VERSION 5.7 ;
  NOWIREEXTENSIONATPIN ON ;
  DIVIDERCHAR "/" ;
  BUSBITCHARS "[]" ;
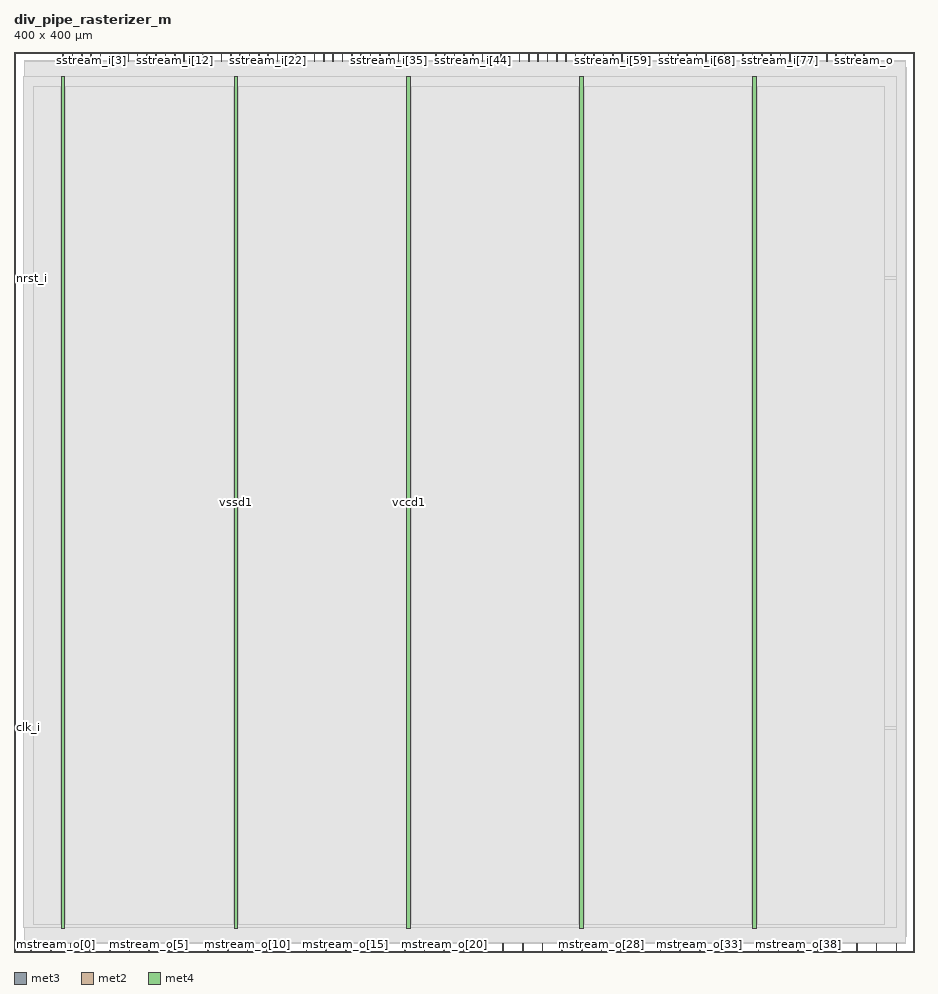
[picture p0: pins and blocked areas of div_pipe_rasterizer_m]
MACRO div_pipe_rasterizer_m
  CLASS BLOCK ;
  FOREIGN div_pipe_rasterizer_m ;
  ORIGIN 0.000 0.000 ;
  SIZE 400.000 BY 400.000 ;
  PIN clk_i
    DIRECTION INPUT ;
    USE SIGNAL ;
    ANTENNAGATEAREA 0.852000 ;
    PORT
      LAYER met3 ;
        RECT 0.000 99.320 4.000 99.920 ;
    END
  END clk_i
  PIN mstream_i
    DIRECTION INPUT ;
    USE SIGNAL ;
    ANTENNAGATEAREA 0.196500 ;
    PORT
      LAYER met2 ;
        RECT 7.450 0.000 7.730 4.000 ;
    END
  END mstream_i
  PIN mstream_o[0]
    DIRECTION OUTPUT TRISTATE ;
    USE SIGNAL ;
    ANTENNADIFFAREA 2.673000 ;
    PORT
      LAYER met2 ;
        RECT 16.190 0.000 16.470 4.000 ;
    END
  END mstream_o[0]
  PIN mstream_o[10]
    DIRECTION OUTPUT TRISTATE ;
    USE SIGNAL ;
    ANTENNADIFFAREA 2.673000 ;
    PORT
      LAYER met2 ;
        RECT 103.590 0.000 103.870 4.000 ;
    END
  END mstream_o[10]
  PIN mstream_o[11]
    DIRECTION OUTPUT TRISTATE ;
    USE SIGNAL ;
    ANTENNADIFFAREA 2.673000 ;
    PORT
      LAYER met2 ;
        RECT 112.330 0.000 112.610 4.000 ;
    END
  END mstream_o[11]
  PIN mstream_o[12]
    DIRECTION OUTPUT TRISTATE ;
    USE SIGNAL ;
    ANTENNADIFFAREA 2.673000 ;
    PORT
      LAYER met2 ;
        RECT 121.070 0.000 121.350 4.000 ;
    END
  END mstream_o[12]
  PIN mstream_o[13]
    DIRECTION OUTPUT TRISTATE ;
    USE SIGNAL ;
    ANTENNADIFFAREA 2.673000 ;
    PORT
      LAYER met2 ;
        RECT 129.810 0.000 130.090 4.000 ;
    END
  END mstream_o[13]
  PIN mstream_o[14]
    DIRECTION OUTPUT TRISTATE ;
    USE SIGNAL ;
    ANTENNADIFFAREA 2.673000 ;
    PORT
      LAYER met2 ;
        RECT 138.550 0.000 138.830 4.000 ;
    END
  END mstream_o[14]
  PIN mstream_o[15]
    DIRECTION OUTPUT TRISTATE ;
    USE SIGNAL ;
    ANTENNADIFFAREA 2.673000 ;
    PORT
      LAYER met2 ;
        RECT 147.290 0.000 147.570 4.000 ;
    END
  END mstream_o[15]
  PIN mstream_o[16]
    DIRECTION OUTPUT TRISTATE ;
    USE SIGNAL ;
    ANTENNADIFFAREA 2.673000 ;
    PORT
      LAYER met2 ;
        RECT 156.030 0.000 156.310 4.000 ;
    END
  END mstream_o[16]
  PIN mstream_o[17]
    DIRECTION OUTPUT TRISTATE ;
    USE SIGNAL ;
    ANTENNADIFFAREA 2.673000 ;
    PORT
      LAYER met2 ;
        RECT 164.770 0.000 165.050 4.000 ;
    END
  END mstream_o[17]
  PIN mstream_o[18]
    DIRECTION OUTPUT TRISTATE ;
    USE SIGNAL ;
    ANTENNADIFFAREA 2.673000 ;
    PORT
      LAYER met2 ;
        RECT 173.510 0.000 173.790 4.000 ;
    END
  END mstream_o[18]
  PIN mstream_o[19]
    DIRECTION OUTPUT TRISTATE ;
    USE SIGNAL ;
    ANTENNADIFFAREA 2.673000 ;
    PORT
      LAYER met2 ;
        RECT 182.250 0.000 182.530 4.000 ;
    END
  END mstream_o[19]
  PIN mstream_o[1]
    DIRECTION OUTPUT TRISTATE ;
    USE SIGNAL ;
    ANTENNADIFFAREA 2.673000 ;
    PORT
      LAYER met2 ;
        RECT 24.930 0.000 25.210 4.000 ;
    END
  END mstream_o[1]
  PIN mstream_o[20]
    DIRECTION OUTPUT TRISTATE ;
    USE SIGNAL ;
    ANTENNADIFFAREA 2.673000 ;
    PORT
      LAYER met2 ;
        RECT 190.990 0.000 191.270 4.000 ;
    END
  END mstream_o[20]
  PIN mstream_o[21]
    DIRECTION OUTPUT TRISTATE ;
    USE SIGNAL ;
    ANTENNADIFFAREA 2.673000 ;
    PORT
      LAYER met2 ;
        RECT 199.730 0.000 200.010 4.000 ;
    END
  END mstream_o[21]
  PIN mstream_o[22]
    DIRECTION OUTPUT TRISTATE ;
    USE SIGNAL ;
    ANTENNADIFFAREA 2.673000 ;
    PORT
      LAYER met2 ;
        RECT 208.470 0.000 208.750 4.000 ;
    END
  END mstream_o[22]
  PIN mstream_o[23]
    DIRECTION OUTPUT TRISTATE ;
    USE SIGNAL ;
    ANTENNADIFFAREA 2.673000 ;
    PORT
      LAYER met2 ;
        RECT 217.210 0.000 217.490 4.000 ;
    END
  END mstream_o[23]
  PIN mstream_o[24]
    DIRECTION OUTPUT TRISTATE ;
    USE SIGNAL ;
    ANTENNADIFFAREA 2.673000 ;
    PORT
      LAYER met2 ;
        RECT 225.950 0.000 226.230 4.000 ;
    END
  END mstream_o[24]
  PIN mstream_o[25]
    DIRECTION OUTPUT TRISTATE ;
    USE SIGNAL ;
    ANTENNADIFFAREA 2.673000 ;
    PORT
      LAYER met2 ;
        RECT 234.690 0.000 234.970 4.000 ;
    END
  END mstream_o[25]
  PIN mstream_o[26]
    DIRECTION OUTPUT TRISTATE ;
    USE SIGNAL ;
    ANTENNADIFFAREA 2.673000 ;
    PORT
      LAYER met2 ;
        RECT 243.430 0.000 243.710 4.000 ;
    END
  END mstream_o[26]
  PIN mstream_o[27]
    DIRECTION OUTPUT TRISTATE ;
    USE SIGNAL ;
    ANTENNADIFFAREA 2.673000 ;
    PORT
      LAYER met2 ;
        RECT 252.170 0.000 252.450 4.000 ;
    END
  END mstream_o[27]
  PIN mstream_o[28]
    DIRECTION OUTPUT TRISTATE ;
    USE SIGNAL ;
    ANTENNADIFFAREA 2.673000 ;
    PORT
      LAYER met2 ;
        RECT 260.910 0.000 261.190 4.000 ;
    END
  END mstream_o[28]
  PIN mstream_o[29]
    DIRECTION OUTPUT TRISTATE ;
    USE SIGNAL ;
    ANTENNADIFFAREA 2.673000 ;
    PORT
      LAYER met2 ;
        RECT 269.650 0.000 269.930 4.000 ;
    END
  END mstream_o[29]
  PIN mstream_o[2]
    DIRECTION OUTPUT TRISTATE ;
    USE SIGNAL ;
    ANTENNADIFFAREA 2.673000 ;
    PORT
      LAYER met2 ;
        RECT 33.670 0.000 33.950 4.000 ;
    END
  END mstream_o[2]
  PIN mstream_o[30]
    DIRECTION OUTPUT TRISTATE ;
    USE SIGNAL ;
    ANTENNADIFFAREA 2.673000 ;
    PORT
      LAYER met2 ;
        RECT 278.390 0.000 278.670 4.000 ;
    END
  END mstream_o[30]
  PIN mstream_o[31]
    DIRECTION OUTPUT TRISTATE ;
    USE SIGNAL ;
    ANTENNADIFFAREA 2.673000 ;
    PORT
      LAYER met2 ;
        RECT 287.130 0.000 287.410 4.000 ;
    END
  END mstream_o[31]
  PIN mstream_o[32]
    DIRECTION OUTPUT TRISTATE ;
    USE SIGNAL ;
    ANTENNADIFFAREA 2.673000 ;
    PORT
      LAYER met2 ;
        RECT 295.870 0.000 296.150 4.000 ;
    END
  END mstream_o[32]
  PIN mstream_o[33]
    DIRECTION OUTPUT TRISTATE ;
    USE SIGNAL ;
    ANTENNADIFFAREA 2.673000 ;
    PORT
      LAYER met2 ;
        RECT 304.610 0.000 304.890 4.000 ;
    END
  END mstream_o[33]
  PIN mstream_o[34]
    DIRECTION OUTPUT TRISTATE ;
    USE SIGNAL ;
    ANTENNADIFFAREA 2.673000 ;
    PORT
      LAYER met2 ;
        RECT 313.350 0.000 313.630 4.000 ;
    END
  END mstream_o[34]
  PIN mstream_o[35]
    DIRECTION OUTPUT TRISTATE ;
    USE SIGNAL ;
    ANTENNADIFFAREA 2.673000 ;
    PORT
      LAYER met2 ;
        RECT 322.090 0.000 322.370 4.000 ;
    END
  END mstream_o[35]
  PIN mstream_o[36]
    DIRECTION OUTPUT TRISTATE ;
    USE SIGNAL ;
    ANTENNADIFFAREA 2.673000 ;
    PORT
      LAYER met2 ;
        RECT 330.830 0.000 331.110 4.000 ;
    END
  END mstream_o[36]
  PIN mstream_o[37]
    DIRECTION OUTPUT TRISTATE ;
    USE SIGNAL ;
    ANTENNADIFFAREA 2.673000 ;
    PORT
      LAYER met2 ;
        RECT 339.570 0.000 339.850 4.000 ;
    END
  END mstream_o[37]
  PIN mstream_o[38]
    DIRECTION OUTPUT TRISTATE ;
    USE SIGNAL ;
    ANTENNADIFFAREA 2.673000 ;
    PORT
      LAYER met2 ;
        RECT 348.310 0.000 348.590 4.000 ;
    END
  END mstream_o[38]
  PIN mstream_o[39]
    DIRECTION OUTPUT TRISTATE ;
    USE SIGNAL ;
    ANTENNADIFFAREA 2.673000 ;
    PORT
      LAYER met2 ;
        RECT 357.050 0.000 357.330 4.000 ;
    END
  END mstream_o[39]
  PIN mstream_o[3]
    DIRECTION OUTPUT TRISTATE ;
    USE SIGNAL ;
    ANTENNADIFFAREA 2.673000 ;
    PORT
      LAYER met2 ;
        RECT 42.410 0.000 42.690 4.000 ;
    END
  END mstream_o[3]
  PIN mstream_o[40]
    DIRECTION OUTPUT TRISTATE ;
    USE SIGNAL ;
    ANTENNADIFFAREA 2.673000 ;
    PORT
      LAYER met2 ;
        RECT 365.790 0.000 366.070 4.000 ;
    END
  END mstream_o[40]
  PIN mstream_o[41]
    DIRECTION OUTPUT TRISTATE ;
    USE SIGNAL ;
    ANTENNADIFFAREA 2.673000 ;
    PORT
      LAYER met2 ;
        RECT 374.530 0.000 374.810 4.000 ;
    END
  END mstream_o[41]
  PIN mstream_o[42]
    DIRECTION OUTPUT TRISTATE ;
    USE SIGNAL ;
    ANTENNADIFFAREA 2.673000 ;
    PORT
      LAYER met2 ;
        RECT 383.270 0.000 383.550 4.000 ;
    END
  END mstream_o[42]
  PIN mstream_o[43]
    DIRECTION OUTPUT TRISTATE ;
    USE SIGNAL ;
    PORT
      LAYER met2 ;
        RECT 392.010 0.000 392.290 4.000 ;
    END
  END mstream_o[43]
  PIN mstream_o[4]
    DIRECTION OUTPUT TRISTATE ;
    USE SIGNAL ;
    ANTENNADIFFAREA 2.673000 ;
    PORT
      LAYER met2 ;
        RECT 51.150 0.000 51.430 4.000 ;
    END
  END mstream_o[4]
  PIN mstream_o[5]
    DIRECTION OUTPUT TRISTATE ;
    USE SIGNAL ;
    ANTENNADIFFAREA 2.673000 ;
    PORT
      LAYER met2 ;
        RECT 59.890 0.000 60.170 4.000 ;
    END
  END mstream_o[5]
  PIN mstream_o[6]
    DIRECTION OUTPUT TRISTATE ;
    USE SIGNAL ;
    ANTENNADIFFAREA 2.673000 ;
    PORT
      LAYER met2 ;
        RECT 68.630 0.000 68.910 4.000 ;
    END
  END mstream_o[6]
  PIN mstream_o[7]
    DIRECTION OUTPUT TRISTATE ;
    USE SIGNAL ;
    ANTENNADIFFAREA 2.673000 ;
    PORT
      LAYER met2 ;
        RECT 77.370 0.000 77.650 4.000 ;
    END
  END mstream_o[7]
  PIN mstream_o[8]
    DIRECTION OUTPUT TRISTATE ;
    USE SIGNAL ;
    ANTENNADIFFAREA 2.673000 ;
    PORT
      LAYER met2 ;
        RECT 86.110 0.000 86.390 4.000 ;
    END
  END mstream_o[8]
  PIN mstream_o[9]
    DIRECTION OUTPUT TRISTATE ;
    USE SIGNAL ;
    ANTENNADIFFAREA 2.673000 ;
    PORT
      LAYER met2 ;
        RECT 94.850 0.000 95.130 4.000 ;
    END
  END mstream_o[9]
  PIN nrst_i
    DIRECTION INPUT ;
    USE SIGNAL ;
    ANTENNAGATEAREA 0.159000 ;
    PORT
      LAYER met3 ;
        RECT 0.000 299.240 4.000 299.840 ;
    END
  END nrst_i
  PIN sstream_i[0]
    DIRECTION INPUT ;
    USE SIGNAL ;
    ANTENNAGATEAREA 0.196500 ;
    PORT
      LAYER met2 ;
        RECT 21.710 396.000 21.990 400.000 ;
    END
  END sstream_i[0]
  PIN sstream_i[10]
    DIRECTION INPUT ;
    USE SIGNAL ;
    ANTENNAGATEAREA 0.196500 ;
    PORT
      LAYER met2 ;
        RECT 63.110 396.000 63.390 400.000 ;
    END
  END sstream_i[10]
  PIN sstream_i[11]
    DIRECTION INPUT ;
    USE SIGNAL ;
    ANTENNAGATEAREA 0.196500 ;
    PORT
      LAYER met2 ;
        RECT 67.250 396.000 67.530 400.000 ;
    END
  END sstream_i[11]
  PIN sstream_i[12]
    DIRECTION INPUT ;
    USE SIGNAL ;
    ANTENNAGATEAREA 0.126000 ;
    PORT
      LAYER met2 ;
        RECT 71.390 396.000 71.670 400.000 ;
    END
  END sstream_i[12]
  PIN sstream_i[13]
    DIRECTION INPUT ;
    USE SIGNAL ;
    ANTENNAGATEAREA 0.126000 ;
    PORT
      LAYER met2 ;
        RECT 75.530 396.000 75.810 400.000 ;
    END
  END sstream_i[13]
  PIN sstream_i[14]
    DIRECTION INPUT ;
    USE SIGNAL ;
    ANTENNAGATEAREA 0.196500 ;
    PORT
      LAYER met2 ;
        RECT 79.670 396.000 79.950 400.000 ;
    END
  END sstream_i[14]
  PIN sstream_i[15]
    DIRECTION INPUT ;
    USE SIGNAL ;
    ANTENNAGATEAREA 0.196500 ;
    PORT
      LAYER met2 ;
        RECT 83.810 396.000 84.090 400.000 ;
    END
  END sstream_i[15]
  PIN sstream_i[16]
    DIRECTION INPUT ;
    USE SIGNAL ;
    ANTENNAGATEAREA 0.196500 ;
    PORT
      LAYER met2 ;
        RECT 87.950 396.000 88.230 400.000 ;
    END
  END sstream_i[16]
  PIN sstream_i[17]
    DIRECTION INPUT ;
    USE SIGNAL ;
    ANTENNAGATEAREA 0.196500 ;
    PORT
      LAYER met2 ;
        RECT 92.090 396.000 92.370 400.000 ;
    END
  END sstream_i[17]
  PIN sstream_i[18]
    DIRECTION INPUT ;
    USE SIGNAL ;
    ANTENNAGATEAREA 0.196500 ;
    PORT
      LAYER met2 ;
        RECT 96.230 396.000 96.510 400.000 ;
    END
  END sstream_i[18]
  PIN sstream_i[19]
    DIRECTION INPUT ;
    USE SIGNAL ;
    ANTENNAGATEAREA 0.196500 ;
    PORT
      LAYER met2 ;
        RECT 100.370 396.000 100.650 400.000 ;
    END
  END sstream_i[19]
  PIN sstream_i[1]
    DIRECTION INPUT ;
    USE SIGNAL ;
    ANTENNAGATEAREA 0.159000 ;
    PORT
      LAYER met2 ;
        RECT 25.850 396.000 26.130 400.000 ;
    END
  END sstream_i[1]
  PIN sstream_i[20]
    DIRECTION INPUT ;
    USE SIGNAL ;
    ANTENNAGATEAREA 0.196500 ;
    PORT
      LAYER met2 ;
        RECT 104.510 396.000 104.790 400.000 ;
    END
  END sstream_i[20]
  PIN sstream_i[21]
    DIRECTION INPUT ;
    USE SIGNAL ;
    ANTENNAGATEAREA 0.196500 ;
    PORT
      LAYER met2 ;
        RECT 108.650 396.000 108.930 400.000 ;
    END
  END sstream_i[21]
  PIN sstream_i[22]
    DIRECTION INPUT ;
    USE SIGNAL ;
    ANTENNAGATEAREA 0.196500 ;
    PORT
      LAYER met2 ;
        RECT 112.790 396.000 113.070 400.000 ;
    END
  END sstream_i[22]
  PIN sstream_i[23]
    DIRECTION INPUT ;
    USE SIGNAL ;
    ANTENNAGATEAREA 0.196500 ;
    PORT
      LAYER met2 ;
        RECT 116.930 396.000 117.210 400.000 ;
    END
  END sstream_i[23]
  PIN sstream_i[24]
    DIRECTION INPUT ;
    USE SIGNAL ;
    ANTENNAGATEAREA 0.196500 ;
    PORT
      LAYER met2 ;
        RECT 121.070 396.000 121.350 400.000 ;
    END
  END sstream_i[24]
  PIN sstream_i[25]
    DIRECTION INPUT ;
    USE SIGNAL ;
    ANTENNAGATEAREA 0.196500 ;
    PORT
      LAYER met2 ;
        RECT 125.210 396.000 125.490 400.000 ;
    END
  END sstream_i[25]
  PIN sstream_i[26]
    DIRECTION INPUT ;
    USE SIGNAL ;
    ANTENNAGATEAREA 0.196500 ;
    PORT
      LAYER met2 ;
        RECT 129.350 396.000 129.630 400.000 ;
    END
  END sstream_i[26]
  PIN sstream_i[27]
    DIRECTION INPUT ;
    USE SIGNAL ;
    ANTENNAGATEAREA 0.196500 ;
    PORT
      LAYER met2 ;
        RECT 133.490 396.000 133.770 400.000 ;
    END
  END sstream_i[27]
  PIN sstream_i[28]
    DIRECTION INPUT ;
    USE SIGNAL ;
    ANTENNAGATEAREA 0.196500 ;
    PORT
      LAYER met2 ;
        RECT 137.630 396.000 137.910 400.000 ;
    END
  END sstream_i[28]
  PIN sstream_i[29]
    DIRECTION INPUT ;
    USE SIGNAL ;
    ANTENNAGATEAREA 0.196500 ;
    PORT
      LAYER met2 ;
        RECT 141.770 396.000 142.050 400.000 ;
    END
  END sstream_i[29]
  PIN sstream_i[2]
    DIRECTION INPUT ;
    USE SIGNAL ;
    ANTENNAGATEAREA 0.213000 ;
    PORT
      LAYER met2 ;
        RECT 29.990 396.000 30.270 400.000 ;
    END
  END sstream_i[2]
  PIN sstream_i[30]
    DIRECTION INPUT ;
    USE SIGNAL ;
    ANTENNAGATEAREA 0.196500 ;
    PORT
      LAYER met2 ;
        RECT 145.910 396.000 146.190 400.000 ;
    END
  END sstream_i[30]
  PIN sstream_i[31]
    DIRECTION INPUT ;
    USE SIGNAL ;
    ANTENNAGATEAREA 0.196500 ;
    PORT
      LAYER met2 ;
        RECT 150.050 396.000 150.330 400.000 ;
    END
  END sstream_i[31]
  PIN sstream_i[32]
    DIRECTION INPUT ;
    USE SIGNAL ;
    ANTENNAGATEAREA 0.196500 ;
    PORT
      LAYER met2 ;
        RECT 154.190 396.000 154.470 400.000 ;
    END
  END sstream_i[32]
  PIN sstream_i[33]
    DIRECTION INPUT ;
    USE SIGNAL ;
    ANTENNAGATEAREA 0.196500 ;
    PORT
      LAYER met2 ;
        RECT 158.330 396.000 158.610 400.000 ;
    END
  END sstream_i[33]
  PIN sstream_i[34]
    DIRECTION INPUT ;
    USE SIGNAL ;
    ANTENNAGATEAREA 0.196500 ;
    PORT
      LAYER met2 ;
        RECT 162.470 396.000 162.750 400.000 ;
    END
  END sstream_i[34]
  PIN sstream_i[35]
    DIRECTION INPUT ;
    USE SIGNAL ;
    ANTENNAGATEAREA 0.196500 ;
    PORT
      LAYER met2 ;
        RECT 166.610 396.000 166.890 400.000 ;
    END
  END sstream_i[35]
  PIN sstream_i[36]
    DIRECTION INPUT ;
    USE SIGNAL ;
    ANTENNAGATEAREA 0.196500 ;
    PORT
      LAYER met2 ;
        RECT 170.750 396.000 171.030 400.000 ;
    END
  END sstream_i[36]
  PIN sstream_i[37]
    DIRECTION INPUT ;
    USE SIGNAL ;
    ANTENNAGATEAREA 0.196500 ;
    PORT
      LAYER met2 ;
        RECT 174.890 396.000 175.170 400.000 ;
    END
  END sstream_i[37]
  PIN sstream_i[38]
    DIRECTION INPUT ;
    USE SIGNAL ;
    ANTENNAGATEAREA 0.196500 ;
    PORT
      LAYER met2 ;
        RECT 179.030 396.000 179.310 400.000 ;
    END
  END sstream_i[38]
  PIN sstream_i[39]
    DIRECTION INPUT ;
    USE SIGNAL ;
    ANTENNAGATEAREA 0.196500 ;
    PORT
      LAYER met2 ;
        RECT 183.170 396.000 183.450 400.000 ;
    END
  END sstream_i[39]
  PIN sstream_i[3]
    DIRECTION INPUT ;
    USE SIGNAL ;
    ANTENNAGATEAREA 0.159000 ;
    PORT
      LAYER met2 ;
        RECT 34.130 396.000 34.410 400.000 ;
    END
  END sstream_i[3]
  PIN sstream_i[40]
    DIRECTION INPUT ;
    USE SIGNAL ;
    ANTENNAGATEAREA 0.196500 ;
    PORT
      LAYER met2 ;
        RECT 187.310 396.000 187.590 400.000 ;
    END
  END sstream_i[40]
  PIN sstream_i[41]
    DIRECTION INPUT ;
    USE SIGNAL ;
    ANTENNAGATEAREA 0.196500 ;
    PORT
      LAYER met2 ;
        RECT 191.450 396.000 191.730 400.000 ;
    END
  END sstream_i[41]
  PIN sstream_i[42]
    DIRECTION INPUT ;
    USE SIGNAL ;
    ANTENNAGATEAREA 0.159000 ;
    PORT
      LAYER met2 ;
        RECT 195.590 396.000 195.870 400.000 ;
    END
  END sstream_i[42]
  PIN sstream_i[43]
    DIRECTION INPUT ;
    USE SIGNAL ;
    ANTENNAGATEAREA 0.196500 ;
    PORT
      LAYER met2 ;
        RECT 199.730 396.000 200.010 400.000 ;
    END
  END sstream_i[43]
  PIN sstream_i[44]
    DIRECTION INPUT ;
    USE SIGNAL ;
    ANTENNAGATEAREA 0.196500 ;
    PORT
      LAYER met2 ;
        RECT 203.870 396.000 204.150 400.000 ;
    END
  END sstream_i[44]
  PIN sstream_i[45]
    DIRECTION INPUT ;
    USE SIGNAL ;
    ANTENNAGATEAREA 0.196500 ;
    PORT
      LAYER met2 ;
        RECT 208.010 396.000 208.290 400.000 ;
    END
  END sstream_i[45]
  PIN sstream_i[46]
    DIRECTION INPUT ;
    USE SIGNAL ;
    ANTENNAGATEAREA 0.196500 ;
    PORT
      LAYER met2 ;
        RECT 212.150 396.000 212.430 400.000 ;
    END
  END sstream_i[46]
  PIN sstream_i[47]
    DIRECTION INPUT ;
    USE SIGNAL ;
    ANTENNAGATEAREA 0.196500 ;
    PORT
      LAYER met2 ;
        RECT 216.290 396.000 216.570 400.000 ;
    END
  END sstream_i[47]
  PIN sstream_i[48]
    DIRECTION INPUT ;
    USE SIGNAL ;
    ANTENNAGATEAREA 0.196500 ;
    PORT
      LAYER met2 ;
        RECT 220.430 396.000 220.710 400.000 ;
    END
  END sstream_i[48]
  PIN sstream_i[49]
    DIRECTION INPUT ;
    USE SIGNAL ;
    ANTENNAGATEAREA 0.196500 ;
    PORT
      LAYER met2 ;
        RECT 224.570 396.000 224.850 400.000 ;
    END
  END sstream_i[49]
  PIN sstream_i[4]
    DIRECTION INPUT ;
    USE SIGNAL ;
    ANTENNAGATEAREA 0.213000 ;
    PORT
      LAYER met2 ;
        RECT 38.270 396.000 38.550 400.000 ;
    END
  END sstream_i[4]
  PIN sstream_i[50]
    DIRECTION INPUT ;
    USE SIGNAL ;
    ANTENNAGATEAREA 0.196500 ;
    PORT
      LAYER met2 ;
        RECT 228.710 396.000 228.990 400.000 ;
    END
  END sstream_i[50]
  PIN sstream_i[51]
    DIRECTION INPUT ;
    USE SIGNAL ;
    ANTENNAGATEAREA 0.196500 ;
    PORT
      LAYER met2 ;
        RECT 232.850 396.000 233.130 400.000 ;
    END
  END sstream_i[51]
  PIN sstream_i[52]
    DIRECTION INPUT ;
    USE SIGNAL ;
    ANTENNAGATEAREA 0.196500 ;
    PORT
      LAYER met2 ;
        RECT 236.990 396.000 237.270 400.000 ;
    END
  END sstream_i[52]
  PIN sstream_i[53]
    DIRECTION INPUT ;
    USE SIGNAL ;
    ANTENNAGATEAREA 0.196500 ;
    PORT
      LAYER met2 ;
        RECT 241.130 396.000 241.410 400.000 ;
    END
  END sstream_i[53]
  PIN sstream_i[54]
    DIRECTION INPUT ;
    USE SIGNAL ;
    ANTENNAGATEAREA 0.196500 ;
    PORT
      LAYER met2 ;
        RECT 245.270 396.000 245.550 400.000 ;
    END
  END sstream_i[54]
  PIN sstream_i[55]
    DIRECTION INPUT ;
    USE SIGNAL ;
    ANTENNAGATEAREA 0.196500 ;
    PORT
      LAYER met2 ;
        RECT 249.410 396.000 249.690 400.000 ;
    END
  END sstream_i[55]
  PIN sstream_i[56]
    DIRECTION INPUT ;
    USE SIGNAL ;
    ANTENNAGATEAREA 0.196500 ;
    PORT
      LAYER met2 ;
        RECT 253.550 396.000 253.830 400.000 ;
    END
  END sstream_i[56]
  PIN sstream_i[57]
    DIRECTION INPUT ;
    USE SIGNAL ;
    ANTENNAGATEAREA 0.196500 ;
    PORT
      LAYER met2 ;
        RECT 257.690 396.000 257.970 400.000 ;
    END
  END sstream_i[57]
  PIN sstream_i[58]
    DIRECTION INPUT ;
    USE SIGNAL ;
    ANTENNAGATEAREA 0.196500 ;
    PORT
      LAYER met2 ;
        RECT 261.830 396.000 262.110 400.000 ;
    END
  END sstream_i[58]
  PIN sstream_i[59]
    DIRECTION INPUT ;
    USE SIGNAL ;
    ANTENNAGATEAREA 0.196500 ;
    PORT
      LAYER met2 ;
        RECT 265.970 396.000 266.250 400.000 ;
    END
  END sstream_i[59]
  PIN sstream_i[5]
    DIRECTION INPUT ;
    USE SIGNAL ;
    ANTENNAGATEAREA 0.196500 ;
    PORT
      LAYER met2 ;
        RECT 42.410 396.000 42.690 400.000 ;
    END
  END sstream_i[5]
  PIN sstream_i[60]
    DIRECTION INPUT ;
    USE SIGNAL ;
    ANTENNAGATEAREA 0.196500 ;
    PORT
      LAYER met2 ;
        RECT 270.110 396.000 270.390 400.000 ;
    END
  END sstream_i[60]
  PIN sstream_i[61]
    DIRECTION INPUT ;
    USE SIGNAL ;
    ANTENNAGATEAREA 0.196500 ;
    PORT
      LAYER met2 ;
        RECT 274.250 396.000 274.530 400.000 ;
    END
  END sstream_i[61]
  PIN sstream_i[62]
    DIRECTION INPUT ;
    USE SIGNAL ;
    ANTENNAGATEAREA 0.196500 ;
    PORT
      LAYER met2 ;
        RECT 278.390 396.000 278.670 400.000 ;
    END
  END sstream_i[62]
  PIN sstream_i[63]
    DIRECTION INPUT ;
    USE SIGNAL ;
    ANTENNAGATEAREA 0.196500 ;
    PORT
      LAYER met2 ;
        RECT 282.530 396.000 282.810 400.000 ;
    END
  END sstream_i[63]
  PIN sstream_i[64]
    DIRECTION INPUT ;
    USE SIGNAL ;
    ANTENNAGATEAREA 0.196500 ;
    PORT
      LAYER met2 ;
        RECT 286.670 396.000 286.950 400.000 ;
    END
  END sstream_i[64]
  PIN sstream_i[65]
    DIRECTION INPUT ;
    USE SIGNAL ;
    ANTENNAGATEAREA 0.196500 ;
    PORT
      LAYER met2 ;
        RECT 290.810 396.000 291.090 400.000 ;
    END
  END sstream_i[65]
  PIN sstream_i[66]
    DIRECTION INPUT ;
    USE SIGNAL ;
    ANTENNAGATEAREA 0.196500 ;
    PORT
      LAYER met2 ;
        RECT 294.950 396.000 295.230 400.000 ;
    END
  END sstream_i[66]
  PIN sstream_i[67]
    DIRECTION INPUT ;
    USE SIGNAL ;
    ANTENNAGATEAREA 0.196500 ;
    PORT
      LAYER met2 ;
        RECT 299.090 396.000 299.370 400.000 ;
    END
  END sstream_i[67]
  PIN sstream_i[68]
    DIRECTION INPUT ;
    USE SIGNAL ;
    ANTENNAGATEAREA 0.196500 ;
    PORT
      LAYER met2 ;
        RECT 303.230 396.000 303.510 400.000 ;
    END
  END sstream_i[68]
  PIN sstream_i[69]
    DIRECTION INPUT ;
    USE SIGNAL ;
    ANTENNAGATEAREA 0.196500 ;
    PORT
      LAYER met2 ;
        RECT 307.370 396.000 307.650 400.000 ;
    END
  END sstream_i[69]
  PIN sstream_i[6]
    DIRECTION INPUT ;
    USE SIGNAL ;
    ANTENNAGATEAREA 0.213000 ;
    PORT
      LAYER met2 ;
        RECT 46.550 396.000 46.830 400.000 ;
    END
  END sstream_i[6]
  PIN sstream_i[70]
    DIRECTION INPUT ;
    USE SIGNAL ;
    ANTENNAGATEAREA 0.196500 ;
    PORT
      LAYER met2 ;
        RECT 311.510 396.000 311.790 400.000 ;
    END
  END sstream_i[70]
  PIN sstream_i[71]
    DIRECTION INPUT ;
    USE SIGNAL ;
    ANTENNAGATEAREA 0.196500 ;
    PORT
      LAYER met2 ;
        RECT 315.650 396.000 315.930 400.000 ;
    END
  END sstream_i[71]
  PIN sstream_i[72]
    DIRECTION INPUT ;
    USE SIGNAL ;
    ANTENNAGATEAREA 0.196500 ;
    PORT
      LAYER met2 ;
        RECT 319.790 396.000 320.070 400.000 ;
    END
  END sstream_i[72]
  PIN sstream_i[73]
    DIRECTION INPUT ;
    USE SIGNAL ;
    ANTENNAGATEAREA 0.196500 ;
    PORT
      LAYER met2 ;
        RECT 323.930 396.000 324.210 400.000 ;
    END
  END sstream_i[73]
  PIN sstream_i[74]
    DIRECTION INPUT ;
    USE SIGNAL ;
    ANTENNAGATEAREA 0.196500 ;
    PORT
      LAYER met2 ;
        RECT 328.070 396.000 328.350 400.000 ;
    END
  END sstream_i[74]
  PIN sstream_i[75]
    DIRECTION INPUT ;
    USE SIGNAL ;
    ANTENNAGATEAREA 0.196500 ;
    PORT
      LAYER met2 ;
        RECT 332.210 396.000 332.490 400.000 ;
    END
  END sstream_i[75]
  PIN sstream_i[76]
    DIRECTION INPUT ;
    USE SIGNAL ;
    ANTENNAGATEAREA 0.196500 ;
    PORT
      LAYER met2 ;
        RECT 336.350 396.000 336.630 400.000 ;
    END
  END sstream_i[76]
  PIN sstream_i[77]
    DIRECTION INPUT ;
    USE SIGNAL ;
    ANTENNAGATEAREA 0.196500 ;
    PORT
      LAYER met2 ;
        RECT 340.490 396.000 340.770 400.000 ;
    END
  END sstream_i[77]
  PIN sstream_i[78]
    DIRECTION INPUT ;
    USE SIGNAL ;
    ANTENNAGATEAREA 0.196500 ;
    PORT
      LAYER met2 ;
        RECT 344.630 396.000 344.910 400.000 ;
    END
  END sstream_i[78]
  PIN sstream_i[79]
    DIRECTION INPUT ;
    USE SIGNAL ;
    ANTENNAGATEAREA 0.196500 ;
    PORT
      LAYER met2 ;
        RECT 348.770 396.000 349.050 400.000 ;
    END
  END sstream_i[79]
  PIN sstream_i[7]
    DIRECTION INPUT ;
    USE SIGNAL ;
    ANTENNAGATEAREA 0.159000 ;
    PORT
      LAYER met2 ;
        RECT 50.690 396.000 50.970 400.000 ;
    END
  END sstream_i[7]
  PIN sstream_i[80]
    DIRECTION INPUT ;
    USE SIGNAL ;
    ANTENNAGATEAREA 0.196500 ;
    PORT
      LAYER met2 ;
        RECT 352.910 396.000 353.190 400.000 ;
    END
  END sstream_i[80]
  PIN sstream_i[81]
    DIRECTION INPUT ;
    USE SIGNAL ;
    ANTENNAGATEAREA 0.196500 ;
    PORT
      LAYER met2 ;
        RECT 357.050 396.000 357.330 400.000 ;
    END
  END sstream_i[81]
  PIN sstream_i[82]
    DIRECTION INPUT ;
    USE SIGNAL ;
    ANTENNAGATEAREA 0.196500 ;
    PORT
      LAYER met2 ;
        RECT 361.190 396.000 361.470 400.000 ;
    END
  END sstream_i[82]
  PIN sstream_i[83]
    DIRECTION INPUT ;
    USE SIGNAL ;
    ANTENNAGATEAREA 0.196500 ;
    PORT
      LAYER met2 ;
        RECT 365.330 396.000 365.610 400.000 ;
    END
  END sstream_i[83]
  PIN sstream_i[84]
    DIRECTION INPUT ;
    USE SIGNAL ;
    ANTENNAGATEAREA 0.196500 ;
    PORT
      LAYER met2 ;
        RECT 369.470 396.000 369.750 400.000 ;
    END
  END sstream_i[84]
  PIN sstream_i[85]
    DIRECTION INPUT ;
    USE SIGNAL ;
    PORT
      LAYER met2 ;
        RECT 373.610 396.000 373.890 400.000 ;
    END
  END sstream_i[85]
  PIN sstream_i[8]
    DIRECTION INPUT ;
    USE SIGNAL ;
    ANTENNAGATEAREA 0.159000 ;
    PORT
      LAYER met2 ;
        RECT 54.830 396.000 55.110 400.000 ;
    END
  END sstream_i[8]
  PIN sstream_i[9]
    DIRECTION INPUT ;
    USE SIGNAL ;
    ANTENNAGATEAREA 0.213000 ;
    PORT
      LAYER met2 ;
        RECT 58.970 396.000 59.250 400.000 ;
    END
  END sstream_i[9]
  PIN sstream_o
    DIRECTION OUTPUT TRISTATE ;
    USE SIGNAL ;
    ANTENNADIFFAREA 2.673000 ;
    PORT
      LAYER met2 ;
        RECT 377.750 396.000 378.030 400.000 ;
    END
  END sstream_o
  PIN vccd1
    DIRECTION INOUT ;
    USE POWER ;
    PORT
      LAYER met4 ;
        RECT 21.040 10.640 22.640 389.200 ;
    END
    PORT
      LAYER met4 ;
        RECT 174.640 10.640 176.240 389.200 ;
    END
    PORT
      LAYER met4 ;
        RECT 328.240 10.640 329.840 389.200 ;
    END
  END vccd1
  PIN vssd1
    DIRECTION INOUT ;
    USE GROUND ;
    PORT
      LAYER met4 ;
        RECT 97.840 10.640 99.440 389.200 ;
    END
    PORT
      LAYER met4 ;
        RECT 251.440 10.640 253.040 389.200 ;
    END
  END vssd1
  OBS
      LAYER li1 ;
        RECT 5.520 10.795 394.220 389.045 ;
      LAYER met1 ;
        RECT 4.670 6.840 396.450 393.000 ;
      LAYER met2 ;
        RECT 4.690 395.720 21.430 396.170 ;
        RECT 22.270 395.720 25.570 396.170 ;
        RECT 26.410 395.720 29.710 396.170 ;
        RECT 30.550 395.720 33.850 396.170 ;
        RECT 34.690 395.720 37.990 396.170 ;
        RECT 38.830 395.720 42.130 396.170 ;
        RECT 42.970 395.720 46.270 396.170 ;
        RECT 47.110 395.720 50.410 396.170 ;
        RECT 51.250 395.720 54.550 396.170 ;
        RECT 55.390 395.720 58.690 396.170 ;
        RECT 59.530 395.720 62.830 396.170 ;
        RECT 63.670 395.720 66.970 396.170 ;
        RECT 67.810 395.720 71.110 396.170 ;
        RECT 71.950 395.720 75.250 396.170 ;
        RECT 76.090 395.720 79.390 396.170 ;
        RECT 80.230 395.720 83.530 396.170 ;
        RECT 84.370 395.720 87.670 396.170 ;
        RECT 88.510 395.720 91.810 396.170 ;
        RECT 92.650 395.720 95.950 396.170 ;
        RECT 96.790 395.720 100.090 396.170 ;
        RECT 100.930 395.720 104.230 396.170 ;
        RECT 105.070 395.720 108.370 396.170 ;
        RECT 109.210 395.720 112.510 396.170 ;
        RECT 113.350 395.720 116.650 396.170 ;
        RECT 117.490 395.720 120.790 396.170 ;
        RECT 121.630 395.720 124.930 396.170 ;
        RECT 125.770 395.720 129.070 396.170 ;
        RECT 129.910 395.720 133.210 396.170 ;
        RECT 134.050 395.720 137.350 396.170 ;
        RECT 138.190 395.720 141.490 396.170 ;
        RECT 142.330 395.720 145.630 396.170 ;
        RECT 146.470 395.720 149.770 396.170 ;
        RECT 150.610 395.720 153.910 396.170 ;
        RECT 154.750 395.720 158.050 396.170 ;
        RECT 158.890 395.720 162.190 396.170 ;
        RECT 163.030 395.720 166.330 396.170 ;
        RECT 167.170 395.720 170.470 396.170 ;
        RECT 171.310 395.720 174.610 396.170 ;
        RECT 175.450 395.720 178.750 396.170 ;
        RECT 179.590 395.720 182.890 396.170 ;
        RECT 183.730 395.720 187.030 396.170 ;
        RECT 187.870 395.720 191.170 396.170 ;
        RECT 192.010 395.720 195.310 396.170 ;
        RECT 196.150 395.720 199.450 396.170 ;
        RECT 200.290 395.720 203.590 396.170 ;
        RECT 204.430 395.720 207.730 396.170 ;
        RECT 208.570 395.720 211.870 396.170 ;
        RECT 212.710 395.720 216.010 396.170 ;
        RECT 216.850 395.720 220.150 396.170 ;
        RECT 220.990 395.720 224.290 396.170 ;
        RECT 225.130 395.720 228.430 396.170 ;
        RECT 229.270 395.720 232.570 396.170 ;
        RECT 233.410 395.720 236.710 396.170 ;
        RECT 237.550 395.720 240.850 396.170 ;
        RECT 241.690 395.720 244.990 396.170 ;
        RECT 245.830 395.720 249.130 396.170 ;
        RECT 249.970 395.720 253.270 396.170 ;
        RECT 254.110 395.720 257.410 396.170 ;
        RECT 258.250 395.720 261.550 396.170 ;
        RECT 262.390 395.720 265.690 396.170 ;
        RECT 266.530 395.720 269.830 396.170 ;
        RECT 270.670 395.720 273.970 396.170 ;
        RECT 274.810 395.720 278.110 396.170 ;
        RECT 278.950 395.720 282.250 396.170 ;
        RECT 283.090 395.720 286.390 396.170 ;
        RECT 287.230 395.720 290.530 396.170 ;
        RECT 291.370 395.720 294.670 396.170 ;
        RECT 295.510 395.720 298.810 396.170 ;
        RECT 299.650 395.720 302.950 396.170 ;
        RECT 303.790 395.720 307.090 396.170 ;
        RECT 307.930 395.720 311.230 396.170 ;
        RECT 312.070 395.720 315.370 396.170 ;
        RECT 316.210 395.720 319.510 396.170 ;
        RECT 320.350 395.720 323.650 396.170 ;
        RECT 324.490 395.720 327.790 396.170 ;
        RECT 328.630 395.720 331.930 396.170 ;
        RECT 332.770 395.720 336.070 396.170 ;
        RECT 336.910 395.720 340.210 396.170 ;
        RECT 341.050 395.720 344.350 396.170 ;
        RECT 345.190 395.720 348.490 396.170 ;
        RECT 349.330 395.720 352.630 396.170 ;
        RECT 353.470 395.720 356.770 396.170 ;
        RECT 357.610 395.720 360.910 396.170 ;
        RECT 361.750 395.720 365.050 396.170 ;
        RECT 365.890 395.720 369.190 396.170 ;
        RECT 370.030 395.720 373.330 396.170 ;
        RECT 374.170 395.720 377.470 396.170 ;
        RECT 378.310 395.720 396.420 396.170 ;
        RECT 4.690 4.280 396.420 395.720 ;
        RECT 4.690 3.670 7.170 4.280 ;
        RECT 8.010 3.670 15.910 4.280 ;
        RECT 16.750 3.670 24.650 4.280 ;
        RECT 25.490 3.670 33.390 4.280 ;
        RECT 34.230 3.670 42.130 4.280 ;
        RECT 42.970 3.670 50.870 4.280 ;
        RECT 51.710 3.670 59.610 4.280 ;
        RECT 60.450 3.670 68.350 4.280 ;
        RECT 69.190 3.670 77.090 4.280 ;
        RECT 77.930 3.670 85.830 4.280 ;
        RECT 86.670 3.670 94.570 4.280 ;
        RECT 95.410 3.670 103.310 4.280 ;
        RECT 104.150 3.670 112.050 4.280 ;
        RECT 112.890 3.670 120.790 4.280 ;
        RECT 121.630 3.670 129.530 4.280 ;
        RECT 130.370 3.670 138.270 4.280 ;
        RECT 139.110 3.670 147.010 4.280 ;
        RECT 147.850 3.670 155.750 4.280 ;
        RECT 156.590 3.670 164.490 4.280 ;
        RECT 165.330 3.670 173.230 4.280 ;
        RECT 174.070 3.670 181.970 4.280 ;
        RECT 182.810 3.670 190.710 4.280 ;
        RECT 191.550 3.670 199.450 4.280 ;
        RECT 200.290 3.670 208.190 4.280 ;
        RECT 209.030 3.670 216.930 4.280 ;
        RECT 217.770 3.670 225.670 4.280 ;
        RECT 226.510 3.670 234.410 4.280 ;
        RECT 235.250 3.670 243.150 4.280 ;
        RECT 243.990 3.670 251.890 4.280 ;
        RECT 252.730 3.670 260.630 4.280 ;
        RECT 261.470 3.670 269.370 4.280 ;
        RECT 270.210 3.670 278.110 4.280 ;
        RECT 278.950 3.670 286.850 4.280 ;
        RECT 287.690 3.670 295.590 4.280 ;
        RECT 296.430 3.670 304.330 4.280 ;
        RECT 305.170 3.670 313.070 4.280 ;
        RECT 313.910 3.670 321.810 4.280 ;
        RECT 322.650 3.670 330.550 4.280 ;
        RECT 331.390 3.670 339.290 4.280 ;
        RECT 340.130 3.670 348.030 4.280 ;
        RECT 348.870 3.670 356.770 4.280 ;
        RECT 357.610 3.670 365.510 4.280 ;
        RECT 366.350 3.670 374.250 4.280 ;
        RECT 375.090 3.670 382.990 4.280 ;
        RECT 383.830 3.670 391.730 4.280 ;
        RECT 392.570 3.670 396.420 4.280 ;
      LAYER met3 ;
        RECT 4.000 300.240 392.315 389.125 ;
        RECT 4.400 298.840 392.315 300.240 ;
        RECT 4.000 100.320 392.315 298.840 ;
        RECT 4.400 98.920 392.315 100.320 ;
        RECT 4.000 10.715 392.315 98.920 ;
      LAYER met4 ;
        RECT 8.575 12.415 20.640 384.705 ;
        RECT 23.040 12.415 97.440 384.705 ;
        RECT 99.840 12.415 174.240 384.705 ;
        RECT 176.640 12.415 251.040 384.705 ;
        RECT 253.440 12.415 327.840 384.705 ;
        RECT 330.240 12.415 387.025 384.705 ;
  END
END div_pipe_rasterizer_m
END LIBRARY

